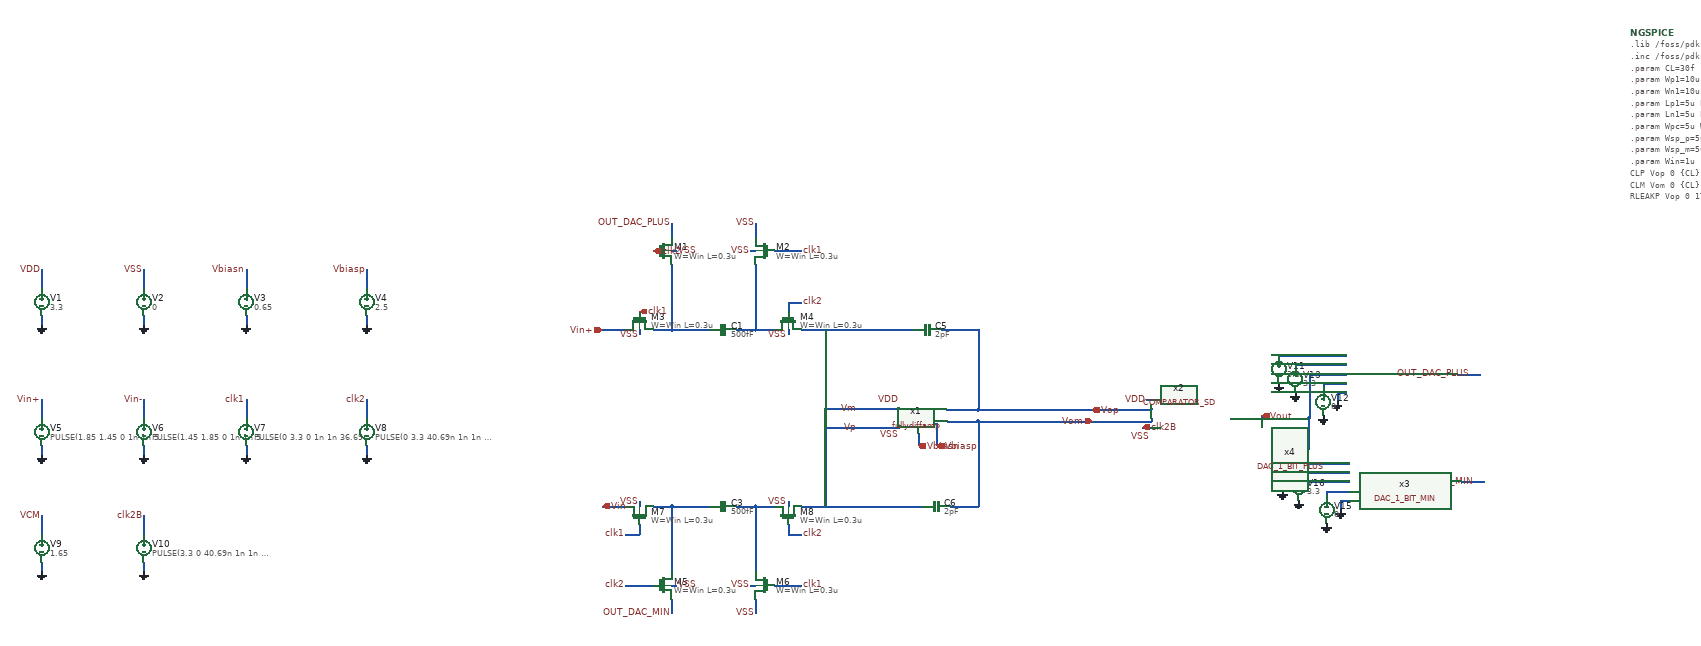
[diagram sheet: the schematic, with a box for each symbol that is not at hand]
v {xschem version=3.4.8RC file_version=1.3}
G {}
K {}
V {}
S {}
F {}
E {}
N -80 -1151.25 -80 -1011.25 {lab=#net1}
N -120 -1011.25 -80 -1011.25 {lab=#net1}
N -80 -1011.25 0 -1011.25 {lab=#net1}
N 60 -1011.25 100 -1011.25 {lab=#net2}
N 100 -1151.25 100 -1011.25 {lab=#net2}
N 100 -1011.25 140 -1011.25 {lab=#net2}
N 200 -1011.25 240 -1011.25 {lab=Vm}
N -200 -1011.25 -180 -1011.25 {lab=Vin+}
N -230 -1011.25 -200 -1011.25 {lab=Vin+}
N 170 -1071.25 170 -1051.25 {lab=clk2}
N 170 -1071.25 200 -1071.25 {lab=clk2}
N 140 -1181.25 200 -1181.25 {lab=clk1}
N 100 -1241.25 100 -1211.25 {lab=VSS}
N -80 -1241.25 -80 -1211.25 {lab=OUT_DAC_PLUS}
N -80 -631.25 -80 -491.25 {lab=#net3}
N -120 -631.25 -80 -631.25 {lab=#net3}
N -80 -631.25 0 -631.25 {lab=#net3}
N 60 -631.25 100 -631.25 {lab=#net4}
N 100 -631.25 100 -491.25 {lab=#net4}
N 100 -631.25 140 -631.25 {lab=#net4}
N 200 -631.25 240 -631.25 {lab=Vp}
N -200 -631.25 -180 -631.25 {lab=Vin-}
N -230 -631.25 -200 -631.25 {lab=Vin-}
N -150 -591.25 -150 -571.25 {lab=clk1}
N -180 -571.25 -150 -571.25 {lab=clk1}
N -180 -461.25 -120 -461.25 {lab=clk2}
N 170 -591.25 170 -571.25 {lab=clk2}
N 170 -571.25 200 -571.25 {lab=clk2}
N 140 -461.25 200 -461.25 {lab=clk1}
N 100 -431.25 100 -401.25 {lab=VSS}
N -80 -431.25 -80 -401.25 {lab=OUT_DAC_MIN}
N -80 -1181.25 -70 -1181.25 {lab=VSS}
N 90 -1181.25 100 -1181.25 {lab=VSS}
N -150 -1011.25 -150 -1001.25 {lab=VSS}
N 170 -1011.25 170 -1001.25 {lab=VSS}
N -150 -641.25 -150 -631.25 {lab=VSS}
N 170 -641.25 170 -631.25 {lab=VSS}
N -80 -461.25 -70 -461.25 {lab=VSS}
N 90 -461.25 100 -461.25 {lab=VSS}
N 240 -1011.25 440 -1011.25 {lab=Vm}
N 240 -631.25 460 -631.25 {lab=Vp}
N 250 -1011.25 250 -841.25 {lab=Vm}
N 250 -841.25 410 -841.25 {lab=Vm}
N 250 -801.25 250 -631.25 {lab=Vp}
N 250 -801.25 410 -801.25 {lab=Vp}
N 410 -806.25 410 -801.25 {lab=Vp}
N 500 -1011.25 570 -1011.25 {lab=Vop}
N 520 -631.25 580 -631.25 {lab=Vom}
N 512.5 -815 580 -815 {lab=Vom}
N 511.25 -838.75 578.75 -838.75 {lab=Vop}
N 570 -1011.25 580 -1011.25 {lab=Vop}
N 578.75 -838.75 580 -838.75 {lab=Vop}
N 580 -1011.25 580 -838.75 {lab=Vop}
N 580 -815 580 -631.25 {lab=Vom}
N 482.5 -808.75 490 -808.75 {lab=Vbiasp}
N 490 -808.75 490 -761.25 {lab=Vbiasp}
N 450 -788.75 450 -761.25 {lab=Vbiasn}
N 580 -838.75 622.5 -838.75 {lab=Vop}
N 580 -815 622.5 -815 {lab=Vom}
N 802.5 -838.75 952.5 -838.75 {lab=Vop}
N 952.5 -841.25 952.5 -838.75 {lab=Vop}
N 802.5 -815 952.5 -815 {lab=Vom}
N 952.5 -821.25 952.5 -815 {lab=Vom}
N 1122.5 -821.25 1292.5 -821.25 {lab=Vout}
N 625 -838.75 672.5 -838.75 {lab=Vop}
N 625 -815 672.5 -815 {lab=Vom}
N 622.5 -838.75 625 -838.75 {lab=Vop}
N 622.5 -815 625 -815 {lab=Vom}
N -1437.5 -1141.25 -1437.5 -1101.25 {lab=VDD}
N -1437.5 -1041.25 -1437.5 -1021.25 {lab=0}
N -1217.5 -1141.25 -1217.5 -1101.25 {lab=VSS}
N -1217.5 -1041.25 -1217.5 -1021.25 {lab=0}
N -997.5 -1141.25 -997.5 -1101.25 {lab=Vbiasn}
N -997.5 -1041.25 -997.5 -1021.25 {lab=0}
N -737.5 -1141.25 -737.5 -1101.25 {lab=Vbiasp}
N -737.5 -1041.25 -737.5 -1021.25 {lab=0}
N -1437.5 -861.25 -1437.5 -821.25 {lab=Vin+}
N -1437.5 -761.25 -1437.5 -741.25 {lab=0}
N -1217.5 -861.25 -1217.5 -821.25 {lab=Vin-}
N -1217.5 -761.25 -1217.5 -741.25 {lab=0}
N -997.5 -861.25 -997.5 -821.25 {lab=clk1}
N -997.5 -761.25 -997.5 -741.25 {lab=0}
N -737.5 -861.25 -737.5 -821.25 {lab=clk2}
N -737.5 -761.25 -737.5 -741.25 {lab=0}
N -1437.5 -611.25 -1437.5 -571.25 {lab=VCM}
N -1437.5 -511.25 -1437.5 -491.25 {lab=0}
N -1217.5 -611.25 -1217.5 -571.25 {lab=clk2B}
N -1217.5 -511.25 -1217.5 -491.25 {lab=0}
N 672.5 -838.75 802.5 -838.75 {lab=Vop}
N 672.5 -815 802.5 -815 {lab=Vom}
N 933.4375 -801.5625 952.5 -801.25 {lab=clk2B}
N 942.1875 -861.25 952.5 -861.25 {lab=VDD}
N 1190 -826.25 1190 -821.25 {lab=Vout}
N 1322.5 -896.25 1372.5 -896.25 {lab=#net5}
N 1322.5 -896.25 1322.5 -886.25 {lab=#net5}
N 1292.5 -916.25 1372.5 -916.25 {lab=Vout}
N 1227.5 -956.25 1372.5 -956.25 {lab=#net6}
N 1292.5 -916.25 1292.5 -821.25 {lab=Vout}
N 1352.5 -876.25 1372.5 -876.25 {lab=0}
N 1352.5 -876.25 1352.5 -856.25 {lab=0}
N 1262.5 -936.25 1372.5 -936.25 {lab=#net7}
N 1330 -663.75 1380 -663.75 {lab=#net8}
N 1330 -663.75 1330 -653.75 {lab=#net8}
N 1300 -683.75 1380 -683.75 {lab=Vout}
N 1235 -723.75 1380 -723.75 {lab=#net9}
N 1360 -643.75 1380 -643.75 {lab=0}
N 1360 -643.75 1360 -623.75 {lab=0}
N 1270 -703.75 1380 -703.75 {lab=#net10}
N 1620 -683.75 1670 -683.75 {lab=OUT_DAC_MIN}
N 1298.75 -683.75 1300 -683.75 {lab=Vout}
N 1290 -683.75 1298.75 -683.75 {lab=Vout}
N 1290 -683.75 1292.5 -821.25 {lab=Vout}
N 1611.25 -916.25 1662.5 -916.25 {lab=OUT_DAC_PLUS}
C {symbols/nfet_03v3.sym} -100 -1181.25 2 1 {name=M1
L=0.3u
W=Win
nf=1
m=1
ad="'int((nf+1)/2) * W/nf * 0.18u'"
pd="'2*int((nf+1)/2) * (W/nf + 0.18u)'"
as="'int((nf+2)/2) * W/nf * 0.18u'"
ps="'2*int((nf+2)/2) * (W/nf + 0.18u)'"
nrd="'0.18u / W'" nrs="'0.18u / W'"
sa=0 sb=0 sd=0
model=nfet_03v3
spiceprefix=X
}
C {symbols/nfet_03v3.sym} 120 -1181.25 2 0 {name=M2
L=0.3u
W=Win
nf=1
m=1
ad="'int((nf+1)/2) * W/nf * 0.18u'"
pd="'2*int((nf+1)/2) * (W/nf + 0.18u)'"
as="'int((nf+2)/2) * W/nf * 0.18u'"
ps="'2*int((nf+2)/2) * (W/nf + 0.18u)'"
nrd="'0.18u / W'" nrs="'0.18u / W'"
sa=0 sb=0 sd=0
model=nfet_03v3
spiceprefix=X
}
C {symbols/nfet_03v3.sym} -150 -1031.25 3 1 {name=M3
L=0.3u
W=Win
nf=1
m=1
ad="'int((nf+1)/2) * W/nf * 0.18u'"
pd="'2*int((nf+1)/2) * (W/nf + 0.18u)'"
as="'int((nf+2)/2) * W/nf * 0.18u'"
ps="'2*int((nf+2)/2) * (W/nf + 0.18u)'"
nrd="'0.18u / W'" nrs="'0.18u / W'"
sa=0 sb=0 sd=0
model=nfet_03v3
spiceprefix=X
}
C {symbols/nfet_03v3.sym} 170 -1031.25 3 1 {name=M4
L=0.3u
W=Win
nf=1
m=1
ad="'int((nf+1)/2) * W/nf * 0.18u'"
pd="'2*int((nf+1)/2) * (W/nf + 0.18u)'"
as="'int((nf+2)/2) * W/nf * 0.18u'"
ps="'2*int((nf+2)/2) * (W/nf + 0.18u)'"
nrd="'0.18u / W'" nrs="'0.18u / W'"
sa=0 sb=0 sd=0
model=nfet_03v3
spiceprefix=X
}
C {capa.sym} 30 -1011.25 1 1 {name=C1
m=1
value=500fF
footprint=1206
device="ceramic capacitor"}
C {ipin.sym} -230 -1011.25 0 0 {name=p3 lab=Vin+}
C {lab_pin.sym} 200 -1181.25 2 0 {name=p1 sig_type=std_logic lab=clk1}
C {lab_pin.sym} 200 -1071.25 2 0 {name=p5 sig_type=std_logic lab=clk2}
C {symbols/nfet_03v3.sym} -100 -461.25 0 0 {name=M5
L=0.3u
W=Win
nf=1
m=1
ad="'int((nf+1)/2) * W/nf * 0.18u'"
pd="'2*int((nf+1)/2) * (W/nf + 0.18u)'"
as="'int((nf+2)/2) * W/nf * 0.18u'"
ps="'2*int((nf+2)/2) * (W/nf + 0.18u)'"
nrd="'0.18u / W'" nrs="'0.18u / W'"
sa=0 sb=0 sd=0
model=nfet_03v3
spiceprefix=X
}
C {symbols/nfet_03v3.sym} 120 -461.25 0 1 {name=M6
L=0.3u
W=Win
nf=1
m=1
ad="'int((nf+1)/2) * W/nf * 0.18u'"
pd="'2*int((nf+1)/2) * (W/nf + 0.18u)'"
as="'int((nf+2)/2) * W/nf * 0.18u'"
ps="'2*int((nf+2)/2) * (W/nf + 0.18u)'"
nrd="'0.18u / W'" nrs="'0.18u / W'"
sa=0 sb=0 sd=0
model=nfet_03v3
spiceprefix=X
}
C {symbols/nfet_03v3.sym} -150 -611.25 3 0 {name=M7
L=0.3u
W=Win
nf=1
m=1
ad="'int((nf+1)/2) * W/nf * 0.18u'"
pd="'2*int((nf+1)/2) * (W/nf + 0.18u)'"
as="'int((nf+2)/2) * W/nf * 0.18u'"
ps="'2*int((nf+2)/2) * (W/nf + 0.18u)'"
nrd="'0.18u / W'" nrs="'0.18u / W'"
sa=0 sb=0 sd=0
model=nfet_03v3
spiceprefix=X
}
C {symbols/nfet_03v3.sym} 170 -611.25 3 0 {name=M8
L=0.3u
W=Win
nf=1
m=1
ad="'int((nf+1)/2) * W/nf * 0.18u'"
pd="'2*int((nf+1)/2) * (W/nf + 0.18u)'"
as="'int((nf+2)/2) * W/nf * 0.18u'"
ps="'2*int((nf+2)/2) * (W/nf + 0.18u)'"
nrd="'0.18u / W'" nrs="'0.18u / W'"
sa=0 sb=0 sd=0
model=nfet_03v3
spiceprefix=X
}
C {capa.sym} 30 -631.25 1 0 {name=C3
m=1
value=500fF
footprint=1206
device="ceramic capacitor"}
C {ipin.sym} -230 -631.25 2 1 {name=p6 lab=Vin-}
C {lab_pin.sym} 200 -461.25 0 1 {name=p7 sig_type=std_logic lab=clk1}
C {lab_pin.sym} -180 -571.25 2 1 {name=p8 sig_type=std_logic lab=clk1}
C {lab_pin.sym} -180 -461.25 2 1 {name=p9 sig_type=std_logic lab=clk2}
C {lab_pin.sym} 200 -571.25 0 1 {name=p10 sig_type=std_logic lab=clk2}
C {lab_pin.sym} -70 -1181.25 2 0 {name=p13 sig_type=std_logic lab=VSS}
C {lab_pin.sym} 90 -1181.25 0 0 {name=p14 sig_type=std_logic lab=VSS}
C {lab_pin.sym} -150 -1001.25 3 0 {name=p15 sig_type=std_logic lab=VSS}
C {lab_pin.sym} 170 -1001.25 3 0 {name=p16 sig_type=std_logic lab=VSS}
C {lab_pin.sym} -150 -641.25 1 0 {name=p17 sig_type=std_logic lab=VSS}
C {lab_pin.sym} 170 -641.25 1 0 {name=p18 sig_type=std_logic lab=VSS}
C {lab_pin.sym} -70 -461.25 2 0 {name=p19 sig_type=std_logic lab=VSS}
C {lab_pin.sym} 90 -461.25 0 0 {name=p20 sig_type=std_logic lab=VSS}
C {capa.sym} 470 -1011.25 3 0 {name=C5
m=1
value=2pF
footprint=1206
device="ceramic capacitor"}
C {capa.sym} 490 -631.25 3 0 {name=C6
m=1
value=2pF
footprint=1206
device="ceramic capacitor"}
C {opin.sym} 825 -838.75 3 0 {name=p11 lab=Vop}
C {opin.sym} 826.25 -815 3 1 {name=p12 lab=Vom}
C {lab_pin.sym} 410 -786.25 0 0 {name=p23 sig_type=std_logic lab=VSS}
C {lab_pin.sym} 410 -861.25 0 0 {name=p24 sig_type=std_logic lab=VDD}
C {lab_pin.sym} 100 -401.25 3 0 {name=p38 sig_type=std_logic lab=VSS}
C {lab_pin.sym} 100 -1241.25 1 0 {name=p39 sig_type=std_logic lab=VSS}
C {ipin.sym} -150 -1051.25 3 1 {name=p41 lab=clk1}
C {ipin.sym} -120 -1181.25 2 1 {name=p2 lab=clk2}
C {ipin.sym} 450 -761.25 1 1 {name=p4 lab=Vbiasn}
C {ipin.sym} 490 -761.25 1 1 {name=p42 lab=Vbiasp}
C {lab_pin.sym} 320 -841.25 1 0 {name=p33 sig_type=std_logic lab=Vm}
C {lab_pin.sym} 320 -801.25 3 0 {name=p34 sig_type=std_logic lab=Vp}
C {lab_pin.sym} 942.1875 -861.25 0 0 {name=p46 sig_type=std_logic lab=VDD}
C {lab_pin.sym} 952.5 -781.25 0 0 {name=p47 sig_type=std_logic lab=VSS}
C {ipin.sym} 933.4375 -801.5625 2 1 {name=p57 lab=clk2B}
C {vsource.sym} -1437.5 -1071.25 0 0 {name=V1 value=3.3 savecurrent=false}
C {gnd.sym} -1437.5 -1021.25 0 0 {name=l5 lab=0}
C {vsource.sym} -1217.5 -1071.25 0 0 {name=V2 value=0 savecurrent=false}
C {gnd.sym} -1217.5 -1021.25 0 0 {name=l6 lab=0}
C {vsource.sym} -997.5 -1071.25 0 0 {name=V3 value=0.65 savecurrent=false}
C {gnd.sym} -997.5 -1021.25 0 0 {name=l7 lab=0}
C {vsource.sym} -737.5 -1071.25 0 0 {name=V4 value=2.5 savecurrent=false}
C {gnd.sym} -737.5 -1021.25 0 0 {name=l8 lab=0}
C {vsource.sym} -1437.5 -791.25 0 0 {name=V5 value="PULSE(1.85 1.45 0 1n 1n 50u 100u)" savecurrent=false}
C {gnd.sym} -1437.5 -741.25 0 0 {name=l9 lab=0}
C {vsource.sym} -1217.5 -791.25 0 0 {name=V6 value="PULSE(1.45 1.85 0 1n 1n 50u 100u)" savecurrent=false}
C {gnd.sym} -1217.5 -741.25 0 0 {name=l10 lab=0}
C {vsource.sym} -997.5 -791.25 0 0 {name=V7 value="PULSE(0 3.3 0 1n 1n 36.69n 81.38n)" savecurrent=false}
C {gnd.sym} -997.5 -741.25 0 0 {name=l11 lab=0}
C {vsource.sym} -737.5 -791.25 0 0 {name=V8 value="PULSE(0 3.3 40.69n 1n 1n 36.69n 81.38n)" savecurrent=false}
C {gnd.sym} -737.5 -741.25 0 0 {name=l12 lab=0}
C {lab_pin.sym} -1437.5 -1141.25 1 0 {name=p25 sig_type=std_logic lab=VDD}
C {lab_pin.sym} -1217.5 -1141.25 1 0 {name=p26 sig_type=std_logic lab=VSS
}
C {lab_pin.sym} -997.5 -1141.25 1 0 {name=p27 sig_type=std_logic lab=Vbiasn
}
C {lab_pin.sym} -737.5 -1141.25 1 0 {name=p28 sig_type=std_logic lab=Vbiasp
}
C {lab_pin.sym} -1437.5 -861.25 1 0 {name=p29 sig_type=std_logic lab=Vin+}
C {lab_pin.sym} -1217.5 -861.25 1 0 {name=p30 sig_type=std_logic lab=Vin-}
C {lab_pin.sym} -997.5 -861.25 1 0 {name=p31 sig_type=std_logic lab=clk1}
C {lab_pin.sym} -737.5 -861.25 1 0 {name=p32 sig_type=std_logic lab=clk2}
C {vsource.sym} -1437.5 -541.25 0 0 {name=V9 value=1.65 savecurrent=false}
C {gnd.sym} -1437.5 -491.25 0 0 {name=l1 lab=0}
C {lab_pin.sym} -1437.5 -611.25 1 0 {name=p35 sig_type=std_logic lab=VCM}
C {devices/code_shown.sym} 1984.375 -1651.875 0 0 {name=NGSPICE only_toplevel=true
value="
.lib /foss/pdks/gf180mcuD/libs.tech/ngspice/sm141064.ngspice typical
.inc /foss/pdks/gf180mcuD/libs.tech/ngspice/design.ngspice

.param CL=30f
.param Wp1=10u Wp2=1u  Wp3=0.5u 
.param Wn1=10u Wn2=10u Wn3=5u   Wn4=0.5u
.param Lp1=5u  Lp2=2u  Lp3=5u
.param Ln1=5u  Ln2=2u  Ln3=0.35u   Ln4=15u
.param Wpc=5u Wnc=2.5u Wsc=2*Wpc Lc=0.3u
.param Wsp_p=5u Wsn_p=0.3u Ld=0.3u Wdp_p=40u Wdn_p=0.6u Wsp2_p=5u Wsn2_p=0.3u
.param Wsp_m=5u Wsn_m=0.5u Wdp_m=10u Wdn_m=1u
.param Win=1u
CLP Vop 0 \{CL\}
CLM Vom 0 \{CL\}
RLEAKP Vop 0 1T
RLEAKM Vom 0 1T

* dummy load supaya tiap node punya DC path ke ground
Rd1 clk1  0 1meg
Rd2 clk2  0 1meg

.control
set color0=white
set color1=black
tran 10u 0.2m
let vicm_ota = (v(Vp)+v(Vm))/2
let vid_ota  = v(Vp)-v(Vm)
let vocm=(v(Vop)-v(Vom))/2
let vod=v(Vop)-v(Vom)
plot vicm_ota vocm
plot vid_ota vod

* --- window ala paper ---
*plot v(clk1) v(clk2)          $ window 1: non-overlapping clocks
*plot v(Vin+)-v(Vin-) v(out2)       $ window 2: input diferensial
*plot v(Vop) v(Vom)            $ window 3: output OTA (single-ended)
plot v(Vop)-v(Vom) v(OUT_DAC_PLUS)           $ window 4: output integrator (diferensial) -> segitiga
plot v(Vop)-v(Vom) v(OUT_DAC_MIN)
*plot v(Vp) v(Vm)
*plot vicm_ota
*plot vid_ota
plot v(Vout) v(Vin+) v(Vin-)
plot v(Vout) v(Vop)-v(Vom)
let inst_pwr = -v(vdd) * i(v1)
meas tran avg_power AVG inst_pwr from=0 to=5u
.endc
.end
"}
C {vsource.sym} -1217.5 -541.25 0 0 {name=V10 value="PULSE(3.3 0 40.69n 1n 1n 36.69n 81.38n)" savecurrent=false}
C {gnd.sym} -1217.5 -491.25 0 0 {name=l2 lab=0}
C {lab_pin.sym} -1217.5 -611.25 1 0 {name=p22 sig_type=std_logic lab=clk2B}
C {latched_comparator/COMPARATOR_SD.sym} 932.5 -661.25 0 0 {name=x2}
C {opin.sym} 1190 -826.25 3 0 {name=p52 lab=Vout}
C {vsource.sym} 1227.5 -926.25 0 0 {name=V11 value=3.3 savecurrent=false}
C {gnd.sym} 1227.5 -896.25 0 0 {name=l3 lab=0}
C {gnd.sym} 1352.5 -856.25 0 0 {name=l4 lab=0}
C {vsource.sym} 1322.5 -856.25 0 0 {name=V12 value=0 savecurrent=false}
C {gnd.sym} 1262.5 -876.25 0 0 {name=l13 lab=0}
C {noconn.sym} 1662.5 -916.25 1 0 {name=l15}
C {vsource.sym} 1262.5 -906.25 0 0 {name=V13 value=3.3 savecurrent=false}
C {gnd.sym} 1322.5 -826.25 0 0 {name=l16 lab=0}
C {vsource.sym} 1235 -693.75 0 0 {name=V14 value=3.3 savecurrent=false}
C {gnd.sym} 1235 -663.75 0 0 {name=l14 lab=0}
C {gnd.sym} 1360 -623.75 0 0 {name=l17 lab=0}
C {vsource.sym} 1330 -623.75 0 0 {name=V15 value=0 savecurrent=false}
C {gnd.sym} 1270 -643.75 0 0 {name=l18 lab=0}
C {lab_pin.sym} 1650 -683.75 1 0 {name=p37 sig_type=std_logic lab=OUT_DAC_MIN}
C {noconn.sym} 1670 -683.75 1 0 {name=l19}
C {vsource.sym} 1270 -673.75 0 0 {name=V16 value=3.3 savecurrent=false}
C {gnd.sym} 1330 -593.75 0 0 {name=l20 lab=0}
C {fully_differential_amplifier/fullydiffamp.sym} 470 -736.25 0 0 {name=x1}
C {dac_1bit/DAC_1_BIT_MIN.sym} 1470 -553.75 0 0 {name=x3}
C {dac_1bit/DAC_1_BIT_PLUS.sym} 1341.25 -826.25 0 0 {name=x4}
C {lab_pin.sym} 1640.625 -916.25 1 0 {name=p40 sig_type=std_logic lab=OUT_DAC_PLUS}
C {lab_pin.sym} -80 -1241.25 1 0 {name=p43 sig_type=std_logic lab=OUT_DAC_PLUS}
C {lab_pin.sym} -80 -401.25 3 0 {name=p36 sig_type=std_logic lab=OUT_DAC_MIN}
